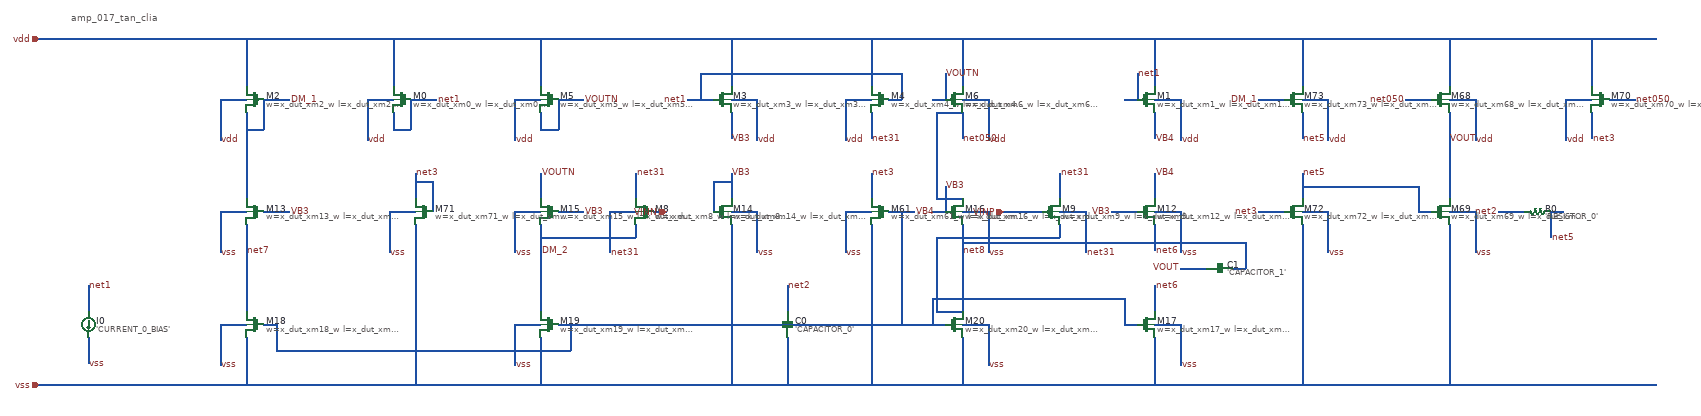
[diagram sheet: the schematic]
v {xschem version=3.4.6 file_version=1.2}
G {}
K {}
V {}
S {}
E {}
T {amp_017_tan_clia} -1615 -200 0 0 0.4 0.4 {}
C {devices/capa_np.sym} 40 520 0 0 {name=C0 value='CAPACITOR_0'}
C {devices/capa_np.sym} 1040 390 1 0 {name=C1 value='CAPACITOR_1'}
C {devices/isource_np.sym} -1575 520 0 0 {name=I0 value='CURRENT_0_BIAS'}
C {devices/res_np.sym} 1775 260 1 0 {name=R0 value='RESISTOR_0'}
C {devices/sg13_lv_pmos_np.sym} -850 0 0 1 {name=M0 model=sg13_lv_pmos spiceprefix=X w=x_dut_xm0_w l=x_dut_xm0_l m=x_dut_xm0_m}
C {devices/sg13_lv_pmos_np.sym} 870 0 0 0 {name=M1 model=sg13_lv_pmos spiceprefix=X w=x_dut_xm1_w l=x_dut_xm1_l m=x_dut_xm1_m}
C {devices/sg13_lv_nmos_np.sym} 870 260 0 0 {name=M12 model=sg13_lv_nmos spiceprefix=X w=x_dut_xm12_w l=x_dut_xm12_l m=x_dut_xm12_m}
C {devices/sg13_lv_nmos_np.sym} -1190 260 0 1 {name=M13 model=sg13_lv_nmos spiceprefix=X w=x_dut_xm13_w l=x_dut_xm13_l m=x_dut_xm13_m}
C {devices/sg13_lv_nmos_np.sym} -110 260 0 0 {name=M14 model=sg13_lv_nmos spiceprefix=X w=x_dut_xm14_w l=x_dut_xm14_l m=x_dut_xm14_m}
C {devices/sg13_lv_nmos_np.sym} -510 260 0 1 {name=M15 model=sg13_lv_nmos spiceprefix=X w=x_dut_xm15_w l=x_dut_xm15_l m=x_dut_xm15_m}
C {devices/sg13_lv_nmos_np.sym} 425 260 0 0 {name=M16 model=sg13_lv_nmos spiceprefix=X w=x_dut_xm16_w l=x_dut_xm16_l m=x_dut_xm16_m}
C {devices/sg13_lv_nmos_np.sym} 870 520 0 0 {name=M17 model=sg13_lv_nmos spiceprefix=X w=x_dut_xm17_w l=x_dut_xm17_l m=x_dut_xm17_m}
C {devices/sg13_lv_nmos_np.sym} -1190 520 0 1 {name=M18 model=sg13_lv_nmos spiceprefix=X w=x_dut_xm18_w l=x_dut_xm18_l m=x_dut_xm18_m}
C {devices/sg13_lv_nmos_np.sym} -510 520 0 1 {name=M19 model=sg13_lv_nmos spiceprefix=X w=x_dut_xm19_w l=x_dut_xm19_l m=x_dut_xm19_m}
C {devices/sg13_lv_pmos_np.sym} -1190 0 0 1 {name=M2 model=sg13_lv_pmos spiceprefix=X w=x_dut_xm2_w l=x_dut_xm2_l m=x_dut_xm2_m}
C {devices/sg13_lv_nmos_np.sym} 425 520 0 0 {name=M20 model=sg13_lv_nmos spiceprefix=X w=x_dut_xm20_w l=x_dut_xm20_l m=x_dut_xm20_m}
C {devices/sg13_lv_pmos_np.sym} -110 0 0 0 {name=M3 model=sg13_lv_pmos spiceprefix=X w=x_dut_xm3_w l=x_dut_xm3_l m=x_dut_xm3_m}
C {devices/sg13_lv_pmos_np.sym} 255 0 0 1 {name=M4 model=sg13_lv_pmos spiceprefix=X w=x_dut_xm4_w l=x_dut_xm4_l m=x_dut_xm4_m}
C {devices/sg13_lv_pmos_np.sym} -510 0 0 1 {name=M5 model=sg13_lv_pmos spiceprefix=X w=x_dut_xm5_w l=x_dut_xm5_l m=x_dut_xm5_m}
C {devices/sg13_lv_pmos_np.sym} 425 0 0 0 {name=M6 model=sg13_lv_pmos spiceprefix=X w=x_dut_xm6_w l=x_dut_xm6_l m=x_dut_xm6_m}
C {devices/sg13_lv_nmos_np.sym} 255 260 0 1 {name=M61 model=sg13_lv_nmos spiceprefix=X w=x_dut_xm61_w l=x_dut_xm61_l m=x_dut_xm61_m}
C {devices/sg13_lv_pmos_np.sym} 1550 0 0 0 {name=M68 model=sg13_lv_pmos spiceprefix=X w=x_dut_xm68_w l=x_dut_xm68_l m=x_dut_xm68_m}
C {devices/sg13_lv_nmos_np.sym} 1550 260 0 0 {name=M69 model=sg13_lv_nmos spiceprefix=X w=x_dut_xm69_w l=x_dut_xm69_l m=x_dut_xm69_m}
C {devices/sg13_lv_pmos_np.sym} 1920 0 0 1 {name=M70 model=sg13_lv_pmos spiceprefix=X w=x_dut_xm70_w l=x_dut_xm70_l m=x_dut_xm70_m}
C {devices/sg13_lv_nmos_np.sym} -800 260 0 1 {name=M71 model=sg13_lv_nmos spiceprefix=X w=x_dut_xm71_w l=x_dut_xm71_l m=x_dut_xm71_m}
C {devices/sg13_lv_nmos_np.sym} 1210 260 0 0 {name=M72 model=sg13_lv_nmos spiceprefix=X w=x_dut_xm72_w l=x_dut_xm72_l m=x_dut_xm72_m}
C {devices/sg13_lv_pmos_np.sym} 1210 0 0 0 {name=M73 model=sg13_lv_pmos spiceprefix=X w=x_dut_xm73_w l=x_dut_xm73_l m=x_dut_xm73_m}
C {devices/sg13_lv_pmos_np.sym} -290 260 0 1 {name=M8 model=sg13_lv_pmos spiceprefix=X w=x_dut_xm8_w l=x_dut_xm8_l m=x_dut_xm8_m}
C {devices/sg13_lv_pmos_np.sym} 650 260 0 0 {name=M9 model=sg13_lv_pmos spiceprefix=X w=x_dut_xm9_w l=x_dut_xm9_l m=x_dut_xm9_m}
N -1575 430 -1575 490 {}
N -1575 550 -1575 610 {}
N -1270 0 -1270 94 {}
N -1270 260 -1270 354 {}
N -1270 520 -1270 614 {}
N -1210 -140 -1210 -30 {}
N -1210 30 -1210 230 {}
N -1210 290 -1210 490 {}
N -1210 550 -1210 660 {}
N -1170 0 -1170 70 {}
N -1140 520 -1140 580 {}
N -930 0 -930 94 {}
N -880 260 -880 354 {}
N -870 -140 -870 -30 {}
N -870 30 -870 70 {}
N -830 0 -830 70 {}
N -820 170 -820 230 {}
N -820 290 -820 660 {}
N -780 190 -780 260 {}
N -590 0 -590 94 {}
N -590 260 -590 354 {}
N -590 520 -590 614 {}
N -530 -140 -530 -30 {}
N -530 30 -530 70 {}
N -530 170 -530 230 {}
N -530 290 -530 490 {}
N -530 550 -530 660 {}
N -490 0 -490 70 {}
N -460 520 -460 580 {}
N -370 260 -370 354 {}
N -310 170 -310 230 {}
N -310 290 -310 320 {}
N -160 -60 -160 0 {}
N -130 190 -130 260 {}
N -90 -140 -90 -30 {}
N -90 30 -90 90 {}
N -90 170 -90 230 {}
N -90 290 -90 660 {}
N -30 0 -30 94 {}
N -30 260 -30 354 {}
N 40 430 40 490 {}
N 40 550 40 660 {}
N 175 0 175 94 {}
N 175 260 175 354 {}
N 235 -140 235 -30 {}
N 235 30 235 90 {}
N 235 170 235 230 {}
N 235 290 235 660 {}
N 305 -60 305 0 {}
N 305 260 305 520 {}
N 375 460 375 520 {}
N 385 30 385 230 {}
N 385 320 385 490 {}
N 405 -60 405 0 {}
N 405 200 405 260 {}
N 445 -140 445 -30 {}
N 445 30 445 90 {}
N 445 290 445 320 {}
N 445 320 445 490 {}
N 445 550 445 660 {}
N 505 0 505 94 {}
N 505 260 505 354 {}
N 505 520 505 614 {}
N 670 170 670 230 {}
N 670 290 670 320 {}
N 730 260 730 354 {}
N 820 460 820 520 {}
N 850 -60 850 0 {}
N 890 -140 890 -30 {}
N 890 30 890 90 {}
N 890 170 890 230 {}
N 890 290 890 350 {}
N 890 430 890 490 {}
N 890 550 890 660 {}
N 950 0 950 94 {}
N 950 260 950 354 {}
N 950 520 950 614 {}
N 1100 330 1100 390 {}
N 1230 -140 1230 -30 {}
N 1230 30 1230 90 {}
N 1230 170 1230 230 {}
N 1230 290 1230 660 {}
N 1290 0 1290 94 {}
N 1290 260 1290 354 {}
N 1500 200 1500 260 {}
N 1570 -140 1570 -30 {}
N 1570 30 1570 230 {}
N 1570 290 1570 660 {}
N 1630 0 1630 94 {}
N 1630 260 1630 354 {}
N 1805 260 1805 320 {}
N 1840 0 1840 94 {}
N 1900 -140 1900 -30 {}
N 1900 30 1900 90 {}
N -1690 -140 2050 -140 {}
N -160 -60 305 -60 {}
N -1270 0 -1210 0 {}
N -1170 0 -1110 0 {}
N -930 0 -870 0 {}
N -830 0 -770 0 {}
N -590 0 -530 0 {}
N -490 0 -430 0 {}
N -190 0 -130 0 {}
N -90 0 -30 0 {}
N 175 0 235 0 {}
N 275 0 305 0 {}
N 375 0 405 0 {}
N 445 0 505 0 {}
N 820 0 850 0 {}
N 890 0 950 0 {}
N 1130 0 1190 0 {}
N 1230 0 1290 0 {}
N 1470 0 1530 0 {}
N 1570 0 1630 0 {}
N 1840 0 1900 0 {}
N 1940 0 2000 0 {}
N 385 30 445 30 {}
N -1210 70 -1170 70 {}
N -870 70 -830 70 {}
N -530 70 -490 70 {}
N -820 190 -780 190 {}
N -130 190 -90 190 {}
N 1230 200 1500 200 {}
N 385 230 445 230 {}
N -1270 260 -1210 260 {}
N -1170 260 -1110 260 {}
N -880 260 -820 260 {}
N -590 260 -530 260 {}
N -490 260 -430 260 {}
N -370 260 -310 260 {}
N -270 260 -240 260 {}
N -90 260 -30 260 {}
N 175 260 235 260 {}
N 275 260 335 260 {}
N 375 260 405 260 {}
N 445 260 505 260 {}
N 540 260 630 260 {}
N 670 260 730 260 {}
N 790 260 850 260 {}
N 890 260 950 260 {}
N 1130 260 1190 260 {}
N 1230 260 1290 260 {}
N 1500 260 1530 260 {}
N 1570 260 1630 260 {}
N 1685 260 1745 260 {}
N 1805 260 1835 260 {}
N -530 320 -310 320 {}
N 385 320 670 320 {}
N 445 330 1100 330 {}
N 950 390 1010 390 {}
N 1070 390 1100 390 {}
N 375 460 820 460 {}
N 385 490 445 490 {}
N -1270 520 -1210 520 {}
N -1170 520 -1140 520 {}
N -590 520 -530 520 {}
N -490 520 405 520 {}
N 445 520 505 520 {}
N 820 520 850 520 {}
N 890 520 950 520 {}
N -1140 580 -460 580 {}
N -1690 660 2050 660 {}
C {devices/lab_wire.sym} -1110 0 0 1 {name=l0 lab=DM_1}
C {devices/lab_wire.sym} 1130 0 0 0 {name=l1 lab=DM_1}
C {devices/lab_wire.sym} -530 350 2 0 {name=l2 lab=DM_2}
C {devices/lab_wire.sym} -1110 260 0 1 {name=l3 lab=VB3}
C {devices/lab_wire.sym} -430 260 0 1 {name=l4 lab=VB3}
C {devices/lab_wire.sym} -90 170 0 1 {name=l5 lab=VB3}
C {devices/lab_wire.sym} -90 90 2 0 {name=l6 lab=VB3}
C {devices/lab_wire.sym} 405 200 0 1 {name=l7 lab=VB3}
C {devices/lab_wire.sym} 790 260 0 0 {name=l8 lab=VB3}
C {devices/lab_wire.sym} 335 260 0 1 {name=l9 lab=VB4}
C {devices/lab_wire.sym} 890 90 2 0 {name=l10 lab=VB4}
C {devices/lab_wire.sym} 890 170 0 1 {name=l11 lab=VB4}
C {devices/lab_wire.sym} 950 390 0 0 {name=l12 lab=VOUT}
C {devices/lab_wire.sym} 1570 90 2 0 {name=l13 lab=VOUT}
C {devices/lab_wire.sym} -430 0 0 1 {name=l14 lab=VOUTN}
C {devices/lab_wire.sym} -530 170 0 1 {name=l15 lab=VOUTN}
C {devices/lab_wire.sym} 405 -60 0 1 {name=l16 lab=VOUTN}
C {devices/lab_wire.sym} 445 90 2 0 {name=l17 lab=net050}
C {devices/lab_wire.sym} 1470 0 0 0 {name=l18 lab=net050}
C {devices/lab_wire.sym} 2000 0 0 1 {name=l19 lab=net050}
C {devices/lab_wire.sym} -770 0 0 1 {name=l20 lab=net1}
C {devices/lab_wire.sym} -190 0 0 0 {name=l21 lab=net1}
C {devices/lab_wire.sym} 850 -60 0 1 {name=l22 lab=net1}
C {devices/lab_wire.sym} 40 430 0 1 {name=l23 lab=net2}
C {devices/lab_wire.sym} 1685 260 0 0 {name=l24 lab=net2}
C {devices/lab_wire.sym} -820 170 0 1 {name=l25 lab=net3}
C {devices/lab_wire.sym} 235 170 0 1 {name=l26 lab=net3}
C {devices/lab_wire.sym} 1130 260 0 0 {name=l27 lab=net3}
C {devices/lab_wire.sym} 1900 90 2 0 {name=l28 lab=net3}
C {devices/lab_wire.sym} -310 170 0 1 {name=l29 lab=net31}
C {devices/lab_wire.sym} 235 90 2 0 {name=l30 lab=net31}
C {devices/lab_wire.sym} 670 170 0 1 {name=l31 lab=net31}
C {devices/lab_wire.sym} 1230 90 2 0 {name=l32 lab=net5}
C {devices/lab_wire.sym} 1230 170 0 1 {name=l33 lab=net5}
C {devices/lab_wire.sym} 1805 320 2 0 {name=l34 lab=net5}
C {devices/lab_wire.sym} 890 350 2 0 {name=l35 lab=net6}
C {devices/lab_wire.sym} 890 430 0 1 {name=l36 lab=net6}
C {devices/lab_wire.sym} -1210 350 2 0 {name=l37 lab=net7}
C {devices/lab_wire.sym} 445 350 2 0 {name=l38 lab=net8}
C {devices/lab_wire.sym} -370 354 2 0 {name=l39 lab=net31}
C {devices/lab_wire.sym} 730 354 2 0 {name=l40 lab=net31}
C {devices/lab_wire.sym} -930 94 2 0 {name=l41 lab=vdd}
C {devices/lab_wire.sym} 950 94 2 0 {name=l42 lab=vdd}
C {devices/lab_wire.sym} -1270 94 2 0 {name=l43 lab=vdd}
C {devices/lab_wire.sym} -30 94 2 0 {name=l44 lab=vdd}
C {devices/lab_wire.sym} 175 94 2 0 {name=l45 lab=vdd}
C {devices/lab_wire.sym} -590 94 2 0 {name=l46 lab=vdd}
C {devices/lab_wire.sym} 505 94 2 0 {name=l47 lab=vdd}
C {devices/lab_wire.sym} 1630 94 2 0 {name=l48 lab=vdd}
C {devices/lab_wire.sym} 1840 94 2 0 {name=l49 lab=vdd}
C {devices/lab_wire.sym} 1290 94 2 0 {name=l50 lab=vdd}
C {devices/lab_wire.sym} 950 354 2 0 {name=l51 lab=vss}
C {devices/lab_wire.sym} -1270 354 2 0 {name=l52 lab=vss}
C {devices/lab_wire.sym} -30 354 2 0 {name=l53 lab=vss}
C {devices/lab_wire.sym} -590 354 2 0 {name=l54 lab=vss}
C {devices/lab_wire.sym} 505 354 2 0 {name=l55 lab=vss}
C {devices/lab_wire.sym} 950 614 2 0 {name=l56 lab=vss}
C {devices/lab_wire.sym} -1270 614 2 0 {name=l57 lab=vss}
C {devices/lab_wire.sym} -590 614 2 0 {name=l58 lab=vss}
C {devices/lab_wire.sym} 505 614 2 0 {name=l59 lab=vss}
C {devices/lab_wire.sym} 175 354 2 0 {name=l60 lab=vss}
C {devices/lab_wire.sym} 1630 354 2 0 {name=l61 lab=vss}
C {devices/lab_wire.sym} -880 354 2 0 {name=l62 lab=vss}
C {devices/lab_wire.sym} 1290 354 2 0 {name=l63 lab=vss}
C {devices/lab_wire.sym} -1575 610 2 0 {name=l64 lab=vss}
C {devices/lab_wire.sym} -1575 430 0 1 {name=l65 lab=net1}
C {devices/ipin.sym} -240 260 0 0 {name=p0 lab=VINN}
C {devices/ipin.sym} 540 260 0 0 {name=p1 lab=VINP}
C {devices/iopin.sym} -1690 -140 0 0 {name=p2 lab=vdd}
C {devices/iopin.sym} -1690 660 0 0 {name=p3 lab=vss}
